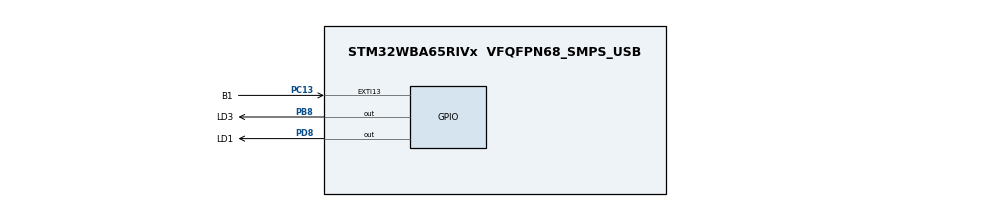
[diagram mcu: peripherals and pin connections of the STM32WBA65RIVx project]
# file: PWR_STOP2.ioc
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CORTEX_M33_NS.userName=CORTEX_M33
Mcu.Family=STM32WBA
Mcu.Name=STM32WBA65RIVx
Mcu.Package=VFQFPN68_SMPS_USB
NVIC.EXTI13_IRQn=true\:0\:0\:false\:false\:true\:true\:true\:true
NVIC.PriorityGroup=NVIC_PRIORITYGROUP_4
OSC_IN.Mode=HSE-External-Oscillator
OSC_IN.PinAttribute=CortexM33
OSC_IN.Signal=RCC_OSC_IN
OSC_OUT.Mode=HSE-External-Oscillator
OSC_OUT.PinAttribute=CortexM33
OSC_OUT.Signal=RCC_OSC_OUT
PB8.GPIO_Label=LD3
PB8.PinAttribute=Free
PB8.PinState=GPIO_PIN_SET
PB8.Signal=GPIO_Output
PC13.GPIO_Label=B1
PC13.GPIO_ModeDefaultEXTI=GPIO_MODE_IT_FALLING
PC13.GPIO_PuPd=GPIO_PULLUP
PC13.PinAttribute=Free
PC13.Signal=GPXTI13
PD8.GPIO_Label=LD1
PD8.PinAttribute=Free
PD8.PinState=GPIO_PIN_SET
PD8.Signal=GPIO_Output
ProjectManager.HeapSize=0x200
ProjectManager.StackSize=0x400
ProjectManager.TargetToolchain=EWARM V9.20
RCC.ADCFreq_Value=100000000
RCC.AHB5CLKDivider=DIV4
RCC.AHBFreq_Value=100000000
RCC.APB1Freq_Value=100000000
RCC.APB1TimFreq_Value=100000000
RCC.APB2Freq_Value=100000000
RCC.APB2TimFreq_Value=100000000
RCC.CortexFreq_Value=12500000
RCC.HCLKFreq_Value=100000000
RCC.HSE_VALUE=32000000
RCC.HSI_VALUE=16000000
RCC.LSE_VALUE=32768
RCC.LSI1_VALUE=32000
RCC.LSI2_VALUE=32000
RCC.PLLFRACN=4096
RCC.PLLM=2
RCC.PLLN=12
RCC.PLLSourceVirtual=RCC_PLLSOURCE_HSE
RCC.SYSCLKFreq_VALUE=100000000
RCC.SYSCLKSourceVirtual=RCC_SYSCLKSOURCE_PLLCLK
RCC.VCOOutputFreq_Value=200000000
VP_CORTEX_M33_NS_VS_Hclk.Mode=Hclk_Mode
VP_ICACHE_VS_ICACHE.Mode=DirectMappedCache
VP_MEMORYMAP_VS_MEMORYMAP.Mode=CurAppReg
VP_PWR_VS_SECSignals.Mode=Security/Privilege
board=custom

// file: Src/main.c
/* USER CODE BEGIN Header */
/**
  ******************************************************************************
  * @file    PWR/PWR_STOP2/Src/main.c
  * @author  MCD Application Team
  * @brief   This sample code shows how to use STM32WBAxx PWR HAL API to enter
  *          and exit the STOP 2 mode.  ******************************************************************************
  * @attention
  *
  * Copyright (c) 2025 STMicroelectronics.
  * All rights reserved.
  *
  * This software is licensed under terms that can be found in the LICENSE file
  * in the root directory of this software component.
  * If no LICENSE file comes with this software, it is provided AS-IS.
  *
  ******************************************************************************
  */
/* USER CODE END Header */
#include "main.h"

/* USER CODE BEGIN PV */
/* Private variables ---------------------------------------------------------*/
#define LED_TOGGLE_DELAY         100
static __IO uint32_t TimingDelay;
/* USER CODE END PV */

void SystemClock_Config(void);
static void MX_GPIO_Init(void);
static void MX_ICACHE_Init(void);

int main(void)
{

  /* MCU Configuration--------------------------------------------------------*/

  /* Reset of all peripherals, Initializes the Flash interface and the Systick. */
  HAL_Init();

  /* USER CODE BEGIN Init */
  /* Configure LD1, and LD3 */
  BSP_LED_Init(LD1);
  BSP_LED_Init(LD3);
  /* USER CODE END Init */

  /* Configure the system clock */
  SystemClock_Config();

  /* USER CODE BEGIN SysInit */

  /* USER push-button (External line 13) will be used to wakeup the system from Stop mode */
  BSP_PB_Init(B1, BUTTON_MODE_EXTI);
  /* USER CODE END SysInit */

  /* Initialize all configured peripherals */
  MX_GPIO_Init();
  MX_ICACHE_Init();
  /* USER CODE BEGIN 2 */

  /* Enable Power Clock */
  __HAL_RCC_PWR_CLK_ENABLE();

  /* Enable Ultra Low Power Mode */
  HAL_PWREx_EnableUltraLowPowerMode();
  /* USER CODE END 2 */

  /* Infinite loop */
  while (1)
  {

    /* USER CODE BEGIN 3 */
    /* Insert 5 second delay */
    HAL_Delay(5000);
    /* Turn OFF LED's */
    BSP_LED_Off(LD1);
    BSP_LED_Off(LD3);

    /*Deactivate Debug of Stop/Standby mode to have the best consumption */

    CLEAR_BIT(DBGMCU->SCR, DBGMCU_SCR_DBG_STOP);
    CLEAR_BIT(DBGMCU->SCR, DBGMCU_SCR_DBG_STANDBY);

    /* Enter STOP 2 mode */
    HAL_PWR_EnterSTOPMode(PWR_LOWPOWERMODE_STOP2, PWR_STOPENTRY_WFI);

    /* Configure system clock after wake-up from STOP: enable HSE, PLL and select
    PLL as system clock source (HSE and PLL are disabled in STOP mode) */
    SystemClock_Config();

    /* ... STOP 2 mode ... */
    /* Configure system clock after wake-up from STOP: enable HSE, PLL and select
    PLL as system clock source (HSE and PLL are disabled in STOP mode) */

  }
  /* USER CODE END 3 */
}

void SystemClock_Config(void)
{
  RCC_OscInitTypeDef RCC_OscInitStruct = {0};
  RCC_ClkInitTypeDef RCC_ClkInitStruct = {0};

  /** Supply configuration update enable
  */
  HAL_PWREx_ConfigSupply(PWR_LDO_SUPPLY);

  /** Configure the main internal regulator output voltage
  */
  if (HAL_PWREx_ControlVoltageScaling(PWR_REGULATOR_VOLTAGE_SCALE1) != HAL_OK)
  {
    Error_Handler();
  }

  /** Initializes the CPU, AHB and APB busses clocks
  */
  RCC_OscInitStruct.OscillatorType = RCC_OSCILLATORTYPE_HSE;
  RCC_OscInitStruct.HSEState = RCC_HSE_ON;
  RCC_OscInitStruct.HSEDiv = RCC_HSE_DIV1;
  RCC_OscInitStruct.PLL1.PLLState = RCC_PLL_ON;
  RCC_OscInitStruct.PLL1.PLLSource = RCC_PLLSOURCE_HSE;
  RCC_OscInitStruct.PLL1.PLLM = 2;
  RCC_OscInitStruct.PLL1.PLLN = 12;
  RCC_OscInitStruct.PLL1.PLLP = 2;
  RCC_OscInitStruct.PLL1.PLLQ = 2;
  RCC_OscInitStruct.PLL1.PLLR = 2;
  RCC_OscInitStruct.PLL1.PLLFractional = 4096;
  if (HAL_RCC_OscConfig(&RCC_OscInitStruct) != HAL_OK)
  {
    Error_Handler();
  }

  /** Initializes the CPU, AHB and APB busses clocks
  */
  RCC_ClkInitStruct.ClockType = RCC_CLOCKTYPE_HCLK|RCC_CLOCKTYPE_SYSCLK
                              |RCC_CLOCKTYPE_PCLK1|RCC_CLOCKTYPE_PCLK2
                              |RCC_CLOCKTYPE_PCLK7|RCC_CLOCKTYPE_HCLK5;
  RCC_ClkInitStruct.SYSCLKSource = RCC_SYSCLKSOURCE_PLLCLK;
  RCC_ClkInitStruct.AHBCLKDivider = RCC_SYSCLK_DIV1;
  RCC_ClkInitStruct.APB1CLKDivider = RCC_HCLK_DIV1;
  RCC_ClkInitStruct.APB2CLKDivider = RCC_HCLK_DIV1;
  RCC_ClkInitStruct.APB7CLKDivider = RCC_HCLK_DIV1;
  RCC_ClkInitStruct.AHB5_PLL1_CLKDivider = RCC_SYSCLK_PLL1_DIV4;
  RCC_ClkInitStruct.AHB5_HSEHSI_CLKDivider = RCC_SYSCLK_HSEHSI_DIV1;

  if (HAL_RCC_ClockConfig(&RCC_ClkInitStruct, FLASH_LATENCY_3) != HAL_OK)
  {
    Error_Handler();
  }
}

static void MX_ICACHE_Init(void)
{

  /** Enable instruction cache in 1-way (direct mapped cache)
  */
  if (HAL_ICACHE_ConfigAssociativityMode(ICACHE_1WAY) != HAL_OK)
  {
    Error_Handler();
  }
  if (HAL_ICACHE_Enable() != HAL_OK)
  {
    Error_Handler();
  }

}

static void MX_GPIO_Init(void)
{
  GPIO_InitTypeDef GPIO_InitStruct = {0};

  /* GPIO Ports Clock Enable */
  __HAL_RCC_GPIOD_CLK_ENABLE();
  __HAL_RCC_GPIOB_CLK_ENABLE();
  __HAL_RCC_GPIOC_CLK_ENABLE();

  /*Configure GPIO pin Output Level */
  HAL_GPIO_WritePin(LD1_GPIO_Port, LD1_Pin, GPIO_PIN_SET);

  /*Configure GPIO pin Output Level */
  HAL_GPIO_WritePin(LD3_GPIO_Port, LD3_Pin, GPIO_PIN_SET);

  /*Configure GPIO pin : LD1_Pin */
  GPIO_InitStruct.Pin = LD1_Pin;
  GPIO_InitStruct.Mode = GPIO_MODE_OUTPUT_PP;
  GPIO_InitStruct.Pull = GPIO_NOPULL;
  GPIO_InitStruct.Speed = GPIO_SPEED_FREQ_LOW;
  HAL_GPIO_Init(LD1_GPIO_Port, &GPIO_InitStruct);

  /*Configure GPIO pin : LD3_Pin */
  GPIO_InitStruct.Pin = LD3_Pin;
  GPIO_InitStruct.Mode = GPIO_MODE_OUTPUT_PP;
  GPIO_InitStruct.Pull = GPIO_NOPULL;
  GPIO_InitStruct.Speed = GPIO_SPEED_FREQ_LOW;
  HAL_GPIO_Init(LD3_GPIO_Port, &GPIO_InitStruct);

  /*Configure GPIO pin : B1_Pin */
  GPIO_InitStruct.Pin = B1_Pin;
  GPIO_InitStruct.Mode = GPIO_MODE_IT_FALLING;
  GPIO_InitStruct.Pull = GPIO_PULLUP;
  HAL_GPIO_Init(B1_GPIO_Port, &GPIO_InitStruct);

  /* EXTI interrupt init*/
  HAL_NVIC_SetPriority(EXTI13_IRQn, 0, 0);
  HAL_NVIC_EnableIRQ(EXTI13_IRQn);

}

/* USER CODE BEGIN 4 */

/**
  * @brief SYSTICK callback
  * @param None
  * @retval None
  */
void HAL_SYSTICK_Callback(void)
{
  if (TimingDelay != 0)
  {
    TimingDelay--;
  }
  else
  {
    /* Toggle LD1 */
    BSP_LED_Toggle(LD1);
    TimingDelay = LED_TOGGLE_DELAY;
  }
}

/**
  * @brief EXTI line detection callbacks
  * @param GPIO_Pin: Specifies the pins connected EXTI line
  * @retval None
  */
void HAL_GPIO_EXTI_Falling_Callback(uint16_t GPIO_Pin)
{
  if (GPIO_Pin == B1_PIN)
  {
    /* Reconfigure LD1 */
    BSP_LED_Init(LD1);
   /* Toggle LD1 */
    BSP_LED_Toggle(LD1);
    TimingDelay = LED_TOGGLE_DELAY;
  }
}

/* USER CODE END 4 */

void Error_Handler(void)
{
  /* USER CODE BEGIN Error_Handler_Debug */
  /* User can add his own implementation to report the HAL error return state */
  __disable_irq();
  BSP_LED_On(LD3);
  while (1)
  {
  }
  /* USER CODE END Error_Handler_Debug */
}
